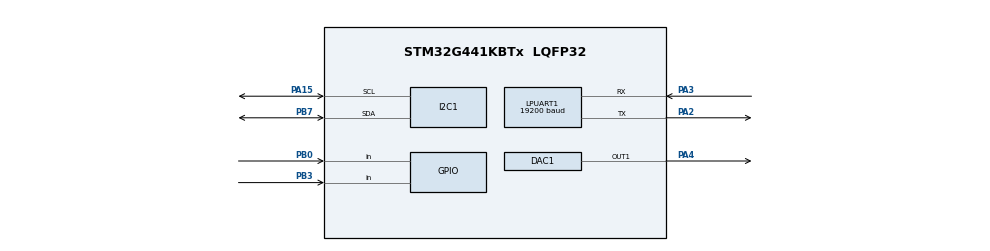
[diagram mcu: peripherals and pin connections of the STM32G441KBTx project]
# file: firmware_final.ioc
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I2C1.Timing=0x10707DBC
LPUART1.BaudRate=19200
Mcu.Family=STM32G4
Mcu.Name=STM32G441KBTx
Mcu.Package=LQFP32
NVIC.PriorityGroup=NVIC_PRIORITYGROUP_4
PA15.GPIO_Pu=GPIO_PULLUP
PA15.Mode=I2C
PA15.Signal=I2C1_SCL
PA2.GPIO_PuPd=GPIO_PULLUP
PA2.Mode=Asynchronous
PA2.Signal=LPUART1_TX
PA3.GPIO_PuPd=GPIO_PULLUP
PA3.Mode=Asynchronous
PA3.Signal=LPUART1_RX
PA4.Signal=COMP_DAC11_group
PB0.Signal=GPIO_Input
PB3.Signal=GPIO_Input
PB7.GPIO_Pu=GPIO_PULLUP
PB7.Mode=I2C
PB7.Signal=I2C1_SDA
ProjectManager.HeapSize=0x200
ProjectManager.StackSize=0x400
ProjectManager.TargetToolchain=STM32CubeIDE
RCC.ADC12Freq_Value=64000000
RCC.AHBFreq_Value=64000000
RCC.APB1Freq_Value=64000000
RCC.APB1TimFreq_Value=64000000
RCC.APB2Freq_Value=64000000
RCC.APB2TimFreq_Value=64000000
RCC.CortexFreq_Value=64000000
RCC.EXTERNAL_CLOCK_VALUE=12288000
RCC.HCLKFreq_Value=64000000
RCC.HSE_VALUE=8000000
RCC.HSI48_VALUE=48000000
RCC.HSI_VALUE=16000000
RCC.LSE_VALUE=32768
RCC.SYSCLKFreq_VALUE=64000000
RCC.SYSCLKSource=RCC_SYSCLKSOURCE_PLLCLK
RCC.USBFreq_Value=64000000
RCC.VCOOutputFreq_Value=128000000
SH.COMP_DAC11_group.0=DAC1_OUT1,DAC_OUT1
TIM2.CounterMode=TIM_COUNTERMODE_DOWN
TIM2.PeriodNoDither=1
TIM2.Prescaler=15999
VP_TIM2_VS_ClockSourceINT.Mode=Internal
board=custom

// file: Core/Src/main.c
/* USER CODE BEGIN Header */
/**
  ******************************************************************************
  * @file           : main.c
  * @brief          : Main program body
  ******************************************************************************
  * @attention
  *
  * Copyright (c) 2023 STMicroelectronics.
  * All rights reserved.
  *
  * This software is licensed under terms that can be found in the LICENSE file
  * in the root directory of this software component.
  * If no LICENSE file comes with this software, it is provided AS-IS.
  *
  ******************************************************************************
  */
/* USER CODE END Header */
#include "main.h"
#include "accelerometer.h"
#include <stdio.h>

DAC_HandleTypeDef hdac1;

I2C_HandleTypeDef hi2c1;

UART_HandleTypeDef hlpuart1;

TIM_HandleTypeDef htim2;

/* USER CODE BEGIN PV */
static volatile struct accelerometer_t xl_r = {.slave_r_addr = ACC0_R_ADDR, .slave_w_addr = ACC0_W_ADDR, .irq_pin = GPIO_PIN_0};
static volatile struct accelerometer_t xl_l = {.slave_r_addr = ACC1_R_ADDR, .slave_w_addr = ACC1_W_ADDR, .irq_pin = GPIO_PIN_1};
static volatile HAL_StatusTypeDef status;
/* USER CODE END PV */

void SystemClock_Config(void);
static void MX_GPIO_Init(void);
static void MX_DAC1_Init(void);
static void MX_I2C1_Init(void);
static void MX_LPUART1_UART_Init(void);
static void MX_TIM2_Init(void);

/* USER CODE BEGIN 0 */

static volatile HAL_StatusTypeDef status;

int _write(int fd, char* ptr, int len) {
  HAL_UART_Transmit(&hlpuart1, (uint8_t *) ptr, len, HAL_MAX_DELAY);
  return len;
}

/* USER CODE END 0 */

int main(void)
{

  /* MCU Configuration--------------------------------------------------------*/

  /* Reset of all peripherals, Initializes the Flash interface and the Systick. */
  HAL_Init();

  /* Configure the system clock */
  SystemClock_Config();

  /* Initialize all configured peripherals */
  MX_GPIO_Init();
  MX_DAC1_Init();
  MX_I2C1_Init();
  MX_LPUART1_UART_Init();
  MX_TIM2_Init();
  /* USER CODE BEGIN 2 */
  acc_init(&xl_l);
  acc_init(&xl_r);
//  HAL_TIM_Base_Start_IT(&htim21);
  /* USER CODE END 2 */

  /* Infinite loop */
  while (1)
  {
	  status = read_axis(&xl_r, ALL_AXIS);
	  status = read_axis(&xl_l, ALL_AXIS);
    /* USER CODE BEGIN 3 */
	if(xl_r.z_xlr < -0x1000)
	{
		printf("hit\r\n");
		HAL_TIM_Base_Start_IT(&htim2);
	}
//	printf("howdy\r\n");
//	printf("%d\r\n",xl_r.x_xlr);
//	printf("%d\r\n",xl_r.y_xlr);
//	printf("%d\r\n",xl_r.z_xlr);
  }
  /* USER CODE END 3 */
}

void SystemClock_Config(void)
{
  RCC_OscInitTypeDef RCC_OscInitStruct = {0};
  RCC_ClkInitTypeDef RCC_ClkInitStruct = {0};

  /** Configure the main internal regulator output voltage
  */
  HAL_PWREx_ControlVoltageScaling(PWR_REGULATOR_VOLTAGE_SCALE1);

  /** Initializes the RCC Oscillators according to the specified parameters
  * in the RCC_OscInitTypeDef structure.
  */
  RCC_OscInitStruct.OscillatorType = RCC_OSCILLATORTYPE_HSI;
  RCC_OscInitStruct.HSIState = RCC_HSI_ON;
  RCC_OscInitStruct.HSICalibrationValue = RCC_HSICALIBRATION_DEFAULT;
  RCC_OscInitStruct.PLL.PLLState = RCC_PLL_NONE;
  if (HAL_RCC_OscConfig(&RCC_OscInitStruct) != HAL_OK)
  {
    Error_Handler();
  }

  /** Initializes the CPU, AHB and APB buses clocks
  */
  RCC_ClkInitStruct.ClockType = RCC_CLOCKTYPE_HCLK|RCC_CLOCKTYPE_SYSCLK
                              |RCC_CLOCKTYPE_PCLK1|RCC_CLOCKTYPE_PCLK2;
  RCC_ClkInitStruct.SYSCLKSource = RCC_SYSCLKSOURCE_HSI;
  RCC_ClkInitStruct.AHBCLKDivider = RCC_SYSCLK_DIV1;
  RCC_ClkInitStruct.APB1CLKDivider = RCC_HCLK_DIV1;
  RCC_ClkInitStruct.APB2CLKDivider = RCC_HCLK_DIV1;

  if (HAL_RCC_ClockConfig(&RCC_ClkInitStruct, FLASH_LATENCY_0) != HAL_OK)
  {
    Error_Handler();
  }
}

static void MX_DAC1_Init(void)
{

  DAC_ChannelConfTypeDef sConfig = {0};

  /** DAC Initialization
  */
  hdac1.Instance = DAC1;
  if (HAL_DAC_Init(&hdac1) != HAL_OK)
  {
    Error_Handler();
  }

  /** DAC channel OUT1 config
  */
  sConfig.DAC_HighFrequency = DAC_HIGH_FREQUENCY_INTERFACE_MODE_AUTOMATIC;
  sConfig.DAC_DMADoubleDataMode = DISABLE;
  sConfig.DAC_SignedFormat = DISABLE;
  sConfig.DAC_SampleAndHold = DAC_SAMPLEANDHOLD_DISABLE;
  sConfig.DAC_Trigger = DAC_TRIGGER_NONE;
  sConfig.DAC_Trigger2 = DAC_TRIGGER_NONE;
  sConfig.DAC_OutputBuffer = DAC_OUTPUTBUFFER_ENABLE;
  sConfig.DAC_ConnectOnChipPeripheral = DAC_CHIPCONNECT_EXTERNAL;
  sConfig.DAC_UserTrimming = DAC_TRIMMING_FACTORY;
  if (HAL_DAC_ConfigChannel(&hdac1, &sConfig, DAC_CHANNEL_1) != HAL_OK)
  {
    Error_Handler();
  }

}

static void MX_I2C1_Init(void)
{

  hi2c1.Instance = I2C1;
  hi2c1.Init.Timing = 0x00303D5B;
  hi2c1.Init.OwnAddress1 = 0;
  hi2c1.Init.AddressingMode = I2C_ADDRESSINGMODE_7BIT;
  hi2c1.Init.DualAddressMode = I2C_DUALADDRESS_DISABLE;
  hi2c1.Init.OwnAddress2 = 0;
  hi2c1.Init.OwnAddress2Masks = I2C_OA2_NOMASK;
  hi2c1.Init.GeneralCallMode = I2C_GENERALCALL_DISABLE;
  hi2c1.Init.NoStretchMode = I2C_NOSTRETCH_DISABLE;
  if (HAL_I2C_Init(&hi2c1) != HAL_OK)
  {
    Error_Handler();
  }

  /** Configure Analogue filter
  */
  if (HAL_I2CEx_ConfigAnalogFilter(&hi2c1, I2C_ANALOGFILTER_ENABLE) != HAL_OK)
  {
    Error_Handler();
  }

  /** Configure Digital filter
  */
  if (HAL_I2CEx_ConfigDigitalFilter(&hi2c1, 0) != HAL_OK)
  {
    Error_Handler();
  }

}

static void MX_LPUART1_UART_Init(void)
{

  hlpuart1.Instance = LPUART1;
  hlpuart1.Init.BaudRate = 19200;
  hlpuart1.Init.WordLength = UART_WORDLENGTH_8B;
  hlpuart1.Init.StopBits = UART_STOPBITS_1;
  hlpuart1.Init.Parity = UART_PARITY_NONE;
  hlpuart1.Init.Mode = UART_MODE_TX_RX;
  hlpuart1.Init.HwFlowCtl = UART_HWCONTROL_NONE;
  hlpuart1.Init.OneBitSampling = UART_ONE_BIT_SAMPLE_DISABLE;
  hlpuart1.Init.ClockPrescaler = UART_PRESCALER_DIV1;
  hlpuart1.AdvancedInit.AdvFeatureInit = UART_ADVFEATURE_NO_INIT;
  if (HAL_UART_Init(&hlpuart1) != HAL_OK)
  {
    Error_Handler();
  }
  if (HAL_UARTEx_SetTxFifoThreshold(&hlpuart1, UART_TXFIFO_THRESHOLD_1_8) != HAL_OK)
  {
    Error_Handler();
  }
  if (HAL_UARTEx_SetRxFifoThreshold(&hlpuart1, UART_RXFIFO_THRESHOLD_1_8) != HAL_OK)
  {
    Error_Handler();
  }
  if (HAL_UARTEx_DisableFifoMode(&hlpuart1) != HAL_OK)
  {
    Error_Handler();
  }

}

static void MX_TIM2_Init(void)
{

  TIM_ClockConfigTypeDef sClockSourceConfig = {0};
  TIM_MasterConfigTypeDef sMasterConfig = {0};

  htim2.Instance = TIM2;
  htim2.Init.Prescaler = 15999;
  htim2.Init.CounterMode = TIM_COUNTERMODE_DOWN;
  htim2.Init.Period = 1;
  htim2.Init.ClockDivision = TIM_CLOCKDIVISION_DIV1;
  htim2.Init.AutoReloadPreload = TIM_AUTORELOAD_PRELOAD_DISABLE;
  if (HAL_TIM_Base_Init(&htim2) != HAL_OK)
  {
    Error_Handler();
  }
  sClockSourceConfig.ClockSource = TIM_CLOCKSOURCE_INTERNAL;
  if (HAL_TIM_ConfigClockSource(&htim2, &sClockSourceConfig) != HAL_OK)
  {
    Error_Handler();
  }
  sMasterConfig.MasterOutputTrigger = TIM_TRGO_RESET;
  sMasterConfig.MasterSlaveMode = TIM_MASTERSLAVEMODE_DISABLE;
  if (HAL_TIMEx_MasterConfigSynchronization(&htim2, &sMasterConfig) != HAL_OK)
  {
    Error_Handler();
  }

}

static void MX_GPIO_Init(void)
{
  GPIO_InitTypeDef GPIO_InitStruct = {0};

  /* GPIO Ports Clock Enable */
  __HAL_RCC_GPIOA_CLK_ENABLE();
  __HAL_RCC_GPIOB_CLK_ENABLE();

  /*Configure GPIO pins : PB0 PB3 */
  GPIO_InitStruct.Pin = GPIO_PIN_0|GPIO_PIN_3;
  GPIO_InitStruct.Mode = GPIO_MODE_INPUT;
  GPIO_InitStruct.Pull = GPIO_NOPULL;
  HAL_GPIO_Init(GPIOB, &GPIO_InitStruct);

}

/* USER CODE BEGIN 4 */
/**
  * @brief Timer Callback function
  * @param htim - the timer that triggered the callback
  * @retval None
  */
void HAL_TIM_PeriodElapsedCallback(TIM_HandleTypeDef *htim)
{

  uint8_t msg[25] = "test\n";

  // Check which version of the timer triggered this callback and toggle LED
  if (htim == &htim2)
  {
	  HAL_GPIO_WritePin(GPIOA, GPIO_PIN_8, GPIO_PIN_SET);
  }
//  if (htim == &htim21)
//  {
//	  status = read_axis(&xl_r, ALL_AXIS);
//	  sprintf(msg, "%d,%d,%d", xl_r.x_xlr, xl_r.y_xlr, xl_r.z_xlr);
//	  HAL_UART_Transmit(&hlpuart1, msg, sizeof(msg), 10);
//  }
}
/* USER CODE END 4 */

void Error_Handler(void)
{
  __disable_irq();
  while (1)
  {
  }
}
